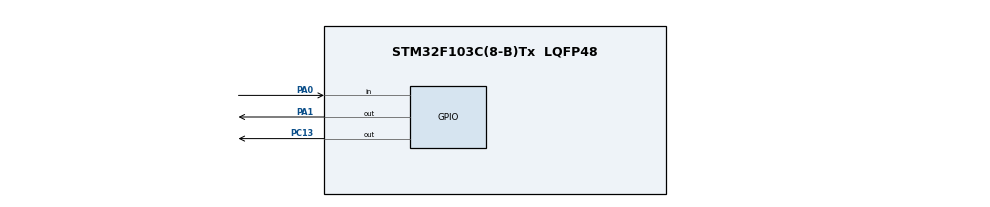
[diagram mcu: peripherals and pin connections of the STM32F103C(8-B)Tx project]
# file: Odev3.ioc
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Mcu.Family=STM32F1
Mcu.Name=STM32F103C(8-B)Tx
Mcu.Package=LQFP48
NVIC.PriorityGroup=NVIC_PRIORITYGROUP_4
NVIC.TIM2_IRQn=true\:0\:0\:false\:false\:true\:true\:true\:true
PA0-WKUP.Signal=GPIO_Input
PA1.Signal=GPIO_Output
PA13.Mode=Serial_Wire
PA13.Signal=SYS_JTMS-SWDIO
PA14.Mode=Serial_Wire
PA14.Signal=SYS_JTCK-SWCLK
PC13-TAMPER-RTC.Signal=GPIO_Output
PD0-OSC_IN.Mode=HSE-External-Oscillator
PD0-OSC_IN.Signal=RCC_OSC_IN
PD1-OSC_OUT.Mode=HSE-External-Oscillator
PD1-OSC_OUT.Signal=RCC_OSC_OUT
ProjectManager.HeapSize=0x200
ProjectManager.StackSize=0x400
ProjectManager.TargetToolchain=Makefile
RCC.APB1Freq_Value=8000000
RCC.APB2Freq_Value=8000000
TIM2.Prescaler=7999
VP_TIM2_VS_ClockSourceINT.Mode=Internal
board=custom

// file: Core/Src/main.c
/* USER CODE BEGIN Header */
/**
  ******************************************************************************
  * @file           : main.c
  * @brief          : Main program body
  ******************************************************************************
  * @attention
  *
  * Copyright (c) 2026 STMicroelectronics.
  * All rights reserved.
  *
  * This software is licensed under terms that can be found in the LICENSE file
  * in the root directory of this software component.
  * If no LICENSE file comes with this software, it is provided AS-IS.
  *
  ******************************************************************************
  */
/* USER CODE END Header */
#include "main.h"

/* USER CODE BEGIN PD */
#define FLASH_STORAGE_ADDR  0x0800FC00
/* USER CODE END PD */

TIM_HandleTypeDef htim2;

/* USER CODE BEGIN PV */
uint32_t blink_count = 4;
volatile uint32_t zamanlayici_tiklamasi = 0;
volatile uint8_t yanip_sonuyor = 1;
volatile uint32_t suanki_yanip = 0;
uint32_t onceki_tik_sayisi = 0;
/* USER CODE END PV */

void SystemClock_Config(void);
static void MX_GPIO_Init(void);
static void MX_TIM2_Init(void);
/* USER CODE BEGIN PFP */
static void Flash_Write(uint32_t value);
/* USER CODE END PFP */

/* USER CODE BEGIN 0 */
static void Flash_Write(uint32_t value)
{
    HAL_FLASH_Unlock();
    FLASH_EraseInitTypeDef e = {0};
    uint32_t err;
    e.TypeErase   = FLASH_TYPEERASE_PAGES;
    e.PageAddress = FLASH_STORAGE_ADDR;
    e.NbPages     = 1;
    HAL_FLASHEx_Erase(&e, &err);
    HAL_FLASH_Program(FLASH_TYPEPROGRAM_WORD, FLASH_STORAGE_ADDR, value);
    HAL_FLASH_Lock();
}
/* USER CODE END 0 */

int main(void)
{

  /* MCU Configuration--------------------------------------------------------*/

  /* Reset of all peripherals, Initializes the Flash interface and the Systick. */
  HAL_Init();

  /* Configure the system clock */
  SystemClock_Config();

  /* Initialize all configured peripherals */
  MX_GPIO_Init();
  MX_TIM2_Init();

  /* USER CODE BEGIN 2 */
  uint32_t flash_val = *(__IO uint32_t *)FLASH_STORAGE_ADDR;

  if (flash_val > 7 || flash_val < 4) {
      blink_count = 4;
      Flash_Write(4);
  } else {
      blink_count = flash_val;
  }

  HAL_GPIO_WritePin(GPIOC, GPIO_PIN_13, GPIO_PIN_SET);

  uint32_t boot_start = HAL_GetTick();
  while (HAL_GPIO_ReadPin(GPIOA, GPIO_PIN_0) == GPIO_PIN_RESET) {
      if (HAL_GetTick() - boot_start >= 3000) {
          blink_count = 4;
          Flash_Write(4);
          while (HAL_GPIO_ReadPin(GPIOA, GPIO_PIN_0) == GPIO_PIN_RESET);
          break;
      }
  }

  HAL_TIM_Base_Start_IT(&htim2);
  /* USER CODE END 2 */

  /* Infinite loop */
  /* USER CODE BEGIN WHILE */
  while (1)
  {
      if (HAL_GPIO_ReadPin(GPIOA, GPIO_PIN_0) == GPIO_PIN_RESET) {
          uint32_t cur_tick = HAL_GetTick();
          if (cur_tick - onceki_tik_sayisi > 300) {
              onceki_tik_sayisi = cur_tick;

              while (HAL_GPIO_ReadPin(GPIOA, GPIO_PIN_0) == GPIO_PIN_RESET);

              if (blink_count >= 7) blink_count = 4;
              else blink_count++;

              Flash_Write(blink_count);

              zamanlayici_tiklamasi   = 0;
              suanki_yanip = 0;
              yanip_sonuyor   = 1;
              HAL_GPIO_WritePin(GPIOC, GPIO_PIN_13, GPIO_PIN_SET);
          }
      }
    /* USER CODE END WHILE */

  }
}

void SystemClock_Config(void)
{
  RCC_OscInitTypeDef RCC_OscInitStruct = {0};
  RCC_ClkInitTypeDef RCC_ClkInitStruct = {0};

  RCC_OscInitStruct.OscillatorType = RCC_OSCILLATORTYPE_HSE;
  RCC_OscInitStruct.HSEState = RCC_HSE_ON;
  RCC_OscInitStruct.HSEPredivValue = RCC_HSE_PREDIV_DIV1;
  RCC_OscInitStruct.HSIState = RCC_HSI_ON;
  RCC_OscInitStruct.PLL.PLLState = RCC_PLL_ON;
  RCC_OscInitStruct.PLL.PLLSource = RCC_PLLSOURCE_HSE;
  RCC_OscInitStruct.PLL.PLLMUL = RCC_PLL_MUL9;
  if (HAL_RCC_OscConfig(&RCC_OscInitStruct) != HAL_OK)
  {
    Error_Handler();
  }

  RCC_ClkInitStruct.ClockType = RCC_CLOCKTYPE_HCLK|RCC_CLOCKTYPE_SYSCLK
                              |RCC_CLOCKTYPE_PCLK1|RCC_CLOCKTYPE_PCLK2;
  RCC_ClkInitStruct.SYSCLKSource = RCC_SYSCLKSOURCE_PLLCLK;
  RCC_ClkInitStruct.AHBCLKDivider = RCC_SYSCLK_DIV1;
  RCC_ClkInitStruct.APB1CLKDivider = RCC_HCLK_DIV2;
  RCC_ClkInitStruct.APB2CLKDivider = RCC_HCLK_DIV1;

  if (HAL_RCC_ClockConfig(&RCC_ClkInitStruct, FLASH_LATENCY_2) != HAL_OK)
  {
    Error_Handler();
  }
}

static void MX_TIM2_Init(void)
{

  TIM_ClockConfigTypeDef sClockSourceConfig = {0};
  TIM_MasterConfigTypeDef sMasterConfig = {0};

  htim2.Instance = TIM2;
  htim2.Init.Prescaler = 7199;
  htim2.Init.CounterMode = TIM_COUNTERMODE_UP;
  htim2.Init.Period = 9999;
  htim2.Init.ClockDivision = TIM_CLOCKDIVISION_DIV1;
  htim2.Init.AutoReloadPreload = TIM_AUTORELOAD_PRELOAD_DISABLE;
  if (HAL_TIM_Base_Init(&htim2) != HAL_OK)
  {
    Error_Handler();
  }
  sClockSourceConfig.ClockSource = TIM_CLOCKSOURCE_INTERNAL;
  if (HAL_TIM_ConfigClockSource(&htim2, &sClockSourceConfig) != HAL_OK)
  {
    Error_Handler();
  }
  sMasterConfig.MasterOutputTrigger = TIM_TRGO_RESET;
  sMasterConfig.MasterSlaveMode = TIM_MASTERSLAVEMODE_DISABLE;
  if (HAL_TIMEx_MasterConfigSynchronization(&htim2, &sMasterConfig) != HAL_OK)
  {
    Error_Handler();
  }
  /* USER CODE BEGIN TIM2_Init 2 */
  HAL_NVIC_SetPriority(TIM2_IRQn, 0, 0);
  HAL_NVIC_EnableIRQ(TIM2_IRQn);
  /* USER CODE END TIM2_Init 2 */

}

static void MX_GPIO_Init(void)
{
  GPIO_InitTypeDef GPIO_InitStruct = {0};

  /* GPIO Ports Clock Enable */
  __HAL_RCC_GPIOC_CLK_ENABLE();
  __HAL_RCC_GPIOD_CLK_ENABLE();
  __HAL_RCC_GPIOA_CLK_ENABLE();

  /*Configure GPIO pin Output Level */
  HAL_GPIO_WritePin(GPIOC, GPIO_PIN_13, GPIO_PIN_SET);

  /*Configure GPIO pin Output Level */
  HAL_GPIO_WritePin(GPIOA, GPIO_PIN_1, GPIO_PIN_RESET);

  /*Configure GPIO pin : PC13 */
  GPIO_InitStruct.Pin = GPIO_PIN_13;
  GPIO_InitStruct.Mode = GPIO_MODE_OUTPUT_PP;
  GPIO_InitStruct.Pull = GPIO_NOPULL;
  GPIO_InitStruct.Speed = GPIO_SPEED_FREQ_LOW;
  HAL_GPIO_Init(GPIOC, &GPIO_InitStruct);

  /*Configure GPIO pin : PA0 */
  GPIO_InitStruct.Pin = GPIO_PIN_0;
  GPIO_InitStruct.Mode = GPIO_MODE_INPUT;
  GPIO_InitStruct.Pull = GPIO_PULLUP;
  HAL_GPIO_Init(GPIOA, &GPIO_InitStruct);

  /*Configure GPIO pin : PA1 */
  GPIO_InitStruct.Pin = GPIO_PIN_1;
  GPIO_InitStruct.Mode = GPIO_MODE_OUTPUT_PP;
  GPIO_InitStruct.Pull = GPIO_NOPULL;
  GPIO_InitStruct.Speed = GPIO_SPEED_FREQ_LOW;
  HAL_GPIO_Init(GPIOA, &GPIO_InitStruct);

}

/* USER CODE BEGIN 4 */
void HAL_TIM_PeriodElapsedCallback(TIM_HandleTypeDef *htim)
{
    if (htim->Instance == TIM2) {
        if (yanip_sonuyor) {
            zamanlayici_tiklamasi++;
            if (zamanlayici_tiklamasi % 2 != 0) {
                HAL_GPIO_WritePin(GPIOC, GPIO_PIN_13, GPIO_PIN_RESET);
            } else {
                HAL_GPIO_WritePin(GPIOC, GPIO_PIN_13, GPIO_PIN_SET);
                suanki_yanip++;
            }
            if (suanki_yanip >= blink_count) {
                yanip_sonuyor   = 0;
                zamanlayici_tiklamasi   = 0;
                suanki_yanip = 0;
                HAL_GPIO_WritePin(GPIOC, GPIO_PIN_13, GPIO_PIN_SET);
            }
        } else {
            zamanlayici_tiklamasi++;
            if (zamanlayici_tiklamasi >= 5) {
                yanip_sonuyor   = 1;
                zamanlayici_tiklamasi   = 0;
                suanki_yanip = 0;
            }
        }
    }
}
/* USER CODE END 4 */

void Error_Handler(void)
{
  __disable_irq();
  while (1)
  {
  }
}
